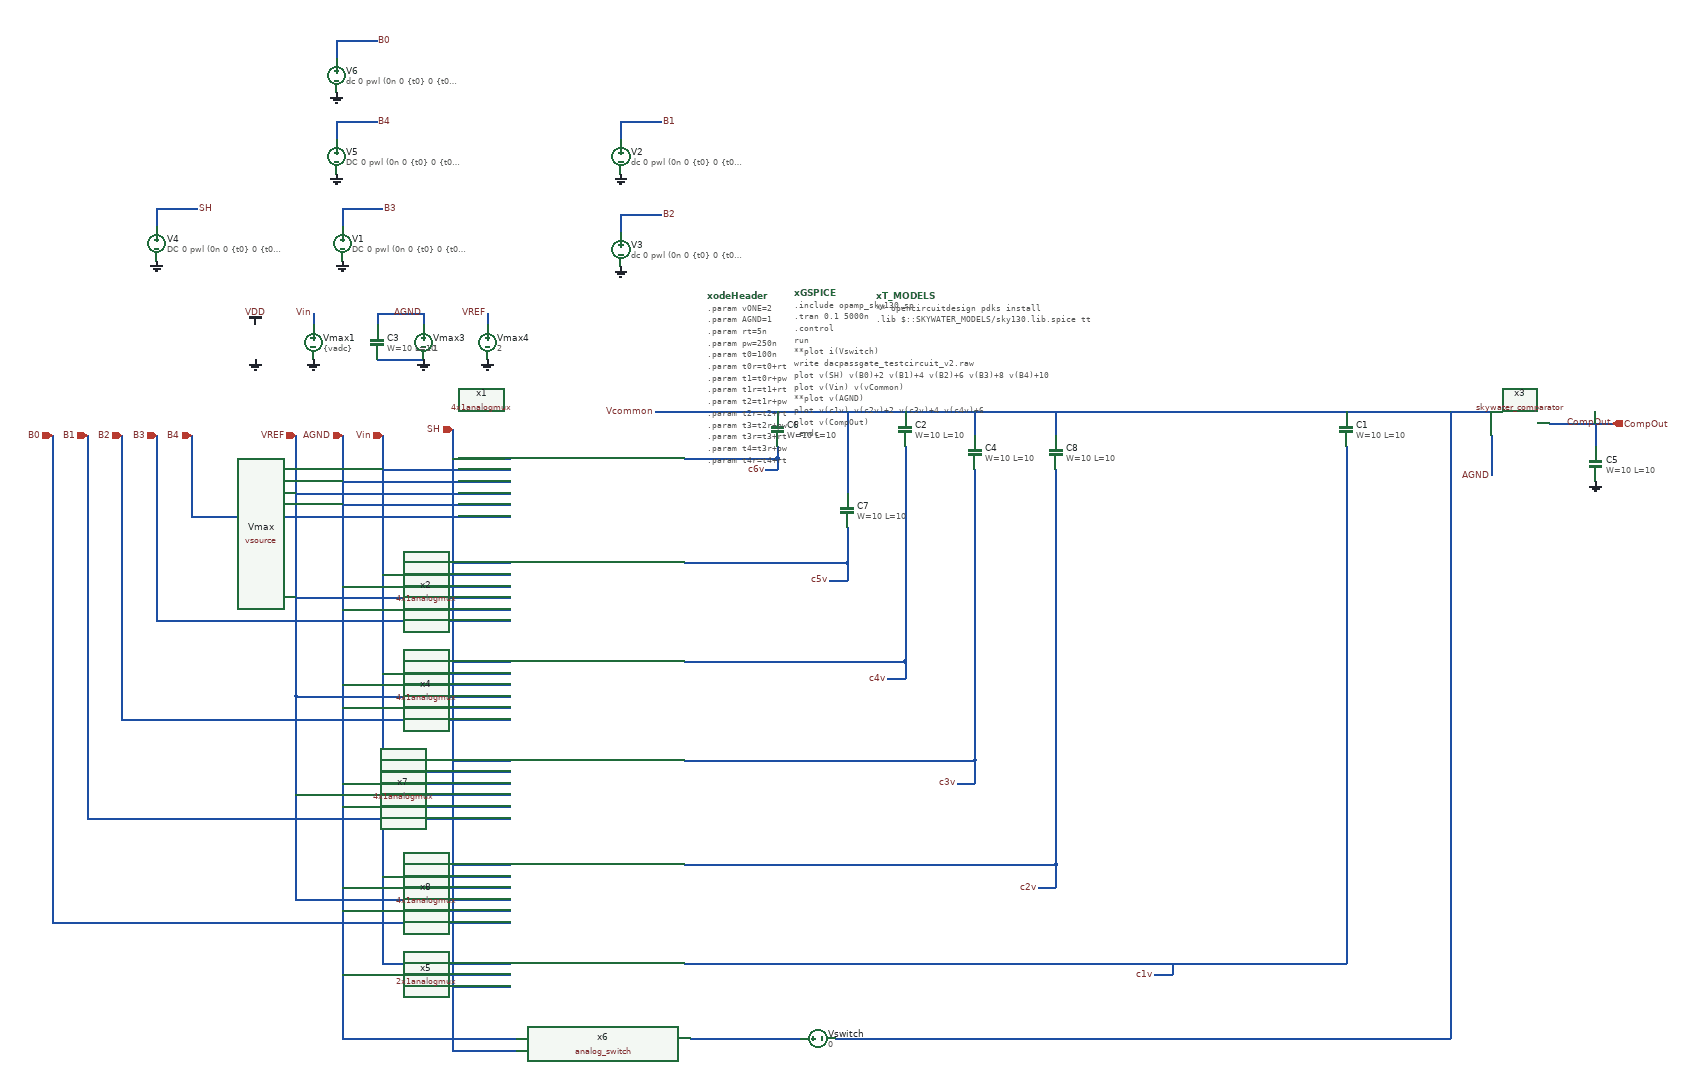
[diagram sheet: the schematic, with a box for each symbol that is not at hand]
v {xschem version=3.0.0 file_version=1.2 

* Copyright 2021 Stefan Frederik Schippers
* 
* Licensed under the Apache License, Version 2.0 (the "License");
* you may not use this file except in compliance with the License.
* You may obtain a copy of the License at
*
*     https://www.apache.org/licenses/LICENSE-2.0
*
* Unless required by applicable law or agreed to in writing, software
* distributed under the License is distributed on an "AS IS" BASIS,
* WITHOUT WARRANTIES OR CONDITIONS OF ANY KIND, either express or implied.
* See the License for the specific language governing permissions and
* limitations under the License.

}
G {}
K {}
V {}
S {}
E {}
N -10 -190 520 -190 { lab=Vcommon}
N 1150 -190 1260 -190 { lab=Vcommon}
N 1260 -150 1260 -80 { lab=AGND}
N 1360 -170 1430 -170 { lab=CompOut}
N -770 -360 -770 -340 { lab=Vin}
N -580 -360 -580 -340 { lab=AGND}
N -1040 -540 -1040 -510 { lab=SH}
N -1040 -540 -970 -540 { lab=SH}
N 1430 -170 1470 -170 { lab=CompOut}
N 1440 -170 1440 -130 { lab=CompOut}
N -470 -360 -470 -340 { lab=VREF}
N -50 -190 -10 -190 { lab=Vcommon}
N 680 780 710 780 { lab=c1v}
N 710 760 710 780 { lab=c1v}
N 250 -130 250 240 { lab=c4v}
N -50 240 250 240 { lab=c4v}
N -720 -540 -720 -510 { lab=B3}
N -720 -540 -650 -540 { lab=B3}
N 250 240 250 270 { lab=c4v}
N 220 270 250 270 { lab=c4v}
N -240 -530 -240 -500 { lab=B2}
N -240 -530 -170 -530 { lab=B2}
N 120 100 140 100 { lab=c5v}
N -50 -110 30 -110 { lab=c6v}
N 30 -130 30 -110 { lab=c6v}
N -730 -690 -730 -660 { lab=B4}
N -730 -690 -660 -690 { lab=B4}
N 30 -110 30 -90 { lab=c6v}
N 10 -90 30 -90 { lab=c6v}
N 150 10 150 70 { lab=c5v}
N 150 -190 150 -50 { lab=Vcommon}
N -180 -190 -50 -190 { lab=Vcommon}
N -650 -150 -650 720 { lab=Vin}
N -720 -150 -720 720 { lab=AGND}
N -530 -160 -530 730 { lab=SH}
N -1040 -150 -1040 160 { lab=B3}
N -1100 -150 -1100 340 { lab=B2}
N -530 -110 -440 -110 { lab=SH}
N -530 70 -430 70 { lab=SH}
N -530 240 -430 240 { lab=SH}
N -980 -10 -440 -10 { lab=B4}
N -1040 170 -430 170 { lab=B3}
N -1100 340 -430 340 { lab=B2}
N -1040 160 -1040 170 { lab=B3}
N -650 -90 -440 -90 { lab=Vin}
N -650 90 -430 90 { lab=Vin}
N -650 260 -430 260 { lab=Vin}
N -130 240 -50 240 { lab=c4v}
N -720 -70 -450 -70 { lab=AGND}
N -450 -70 -440 -70 { lab=AGND}
N -720 110 -430 110 { lab=AGND}
N -720 280 -430 280 { lab=AGND}
N -720 -30 -440 -30 { lab=AGND}
N -800 -50 -440 -50 { lab=VREF}
N -720 150 -430 150 { lab=AGND}
N -800 130 -430 130 { lab=VREF}
N -800 300 -430 300 { lab=VREF}
N -720 320 -430 320 { lab=AGND}
N -800 -150 -800 300 { lab=VREF}
N -120 890 -50 890 { lab=#net1}
N -980 -150 -980 -10 { lab=B4}
N 150 70 150 100 { lab=c5v}
N 140 100 150 100 { lab=c5v}
N -40 70 150 70 { lab=c5v}
N -50 890 70 890 { lab=#net1}
N -660 -360 -580 -360 { lab=AGND}
N -660 -360 -660 -340 { lab=AGND}
N -660 -280 -580 -280 { lab=GND}
N -130 760 380 760 {
lab=c1v}
N 130 890 580 890 {
lab=Vcommon}
N -720 780 -430 780 {
lab=AGND}
N -720 890 -420 890 {
lab=AGND}
N -720 720 -720 890 {
lab=AGND}
N -650 760 -430 760 {
lab=Vin}
N -650 720 -650 760 {
lab=Vin}
N -530 800 -430 800 {
lab=SH}
N -530 910 -420 910 {
lab=SH}
N -530 730 -530 910 {
lab=SH}
N -530 410 -430 410 {
lab=SH}
N -530 590 -430 590 {
lab=SH}
N -650 610 -430 610 {
lab=Vin}
N -130 410 370 410 {
lab=c3v}
N 370 -90 370 410 {
lab=c3v}
N 370 -190 370 -150 {
lab=Vcommon}
N 520 -190 1150 -190 {
lab=Vcommon}
N -130 590 510 590 {
lab=c2v}
N 510 -90 510 590 {
lab=c2v}
N 510 -190 510 -150 {
lab=Vcommon}
N -650 430 -430 430 {
lab=Vin}
N -720 450 -430 450 {
lab=AGND}
N -720 630 -430 630 {
lab=AGND}
N -720 490 -430 490 {
lab=AGND}
N -720 670 -430 670 {
lab=AGND}
N -800 650 -430 650 {
lab=VREF}
N -800 300 -800 650 {
lab=VREF}
N -800 470 -430 470 {
lab=VREF}
N -1160 510 -430 510 {
lab=B1}
N -1160 -150 -1160 510 {
lab=B1}
N -1220 690 -430 690 {
lab=B0}
N -1220 -150 -1220 690 {
lab=B0}
N 580 890 1190 890 {
lab=Vcommon}
N 1190 -190 1190 890 {
lab=Vcommon}
N 510 590 510 610 { lab=c2v}
N 480 630 510 630 { lab=c2v}
N 510 610 510 630 { lab=c2v}
N 370 410 370 430 { lab=c3v}
N 340 450 370 450 { lab=c3v}
N 370 430 370 450 { lab=c3v}
N 380 760 1010 760 {
lab=c1v}
N 1010 -130 1010 760 {
lab=c1v}
N -240 -690 -240 -660 { lab=B1}
N -240 -690 -170 -690 { lab=B1}
N -730 -830 -730 -800 { lab=B0}
N -730 -830 -660 -830 { lab=B0}
N -440 -110 -430 -110 {
lab=SH}
N -440 -90 -430 -90 {
lab=Vin}
N -440 -70 -430 -70 {
lab=AGND}
N -440 -50 -430 -50 {
lab=VREF}
N -440 -30 -430 -30 {
lab=AGND}
N -440 -10 -430 -10 {
lab=B4}
N -130 -110 -50 -110 {
lab=c6v}
N -130 70 -40 70 {
lab=c5v}
C {symbols/code.sym} 60 -395 0 0 {name=xGSPICE
only_toplevel=true
value="
.include "opamp_sky130.sp"

.tran 0.1 5000n
.control
run
**plot i(Vswitch)
write dacpassgate_testcircuit_v2.raw
plot v(SH) v(B0)+2 v(B1)+4 v(B2)+6 v(B3)+8 v(B4)+10
plot v(Vin)  v(vCommon) 
**plot v(AGND)
plot v(c1v) v(c2v)+2 v(c3v)+4 v(c4v)+6
plot v(CompOut)
.endc
" }
C {symbols/code.sym} 200 -390 0 0 {name=xT_MODELS
only_toplevel=true
format="tcleval( @value )"
value="
** opencircuitdesign pdks install
.lib $::SKYWATER_MODELS/sky130.lib.spice tt

"
spice_ignore=false}
C {symbols/vsource.sym} -870 -310 0 0 {name=Vmax value=2}
C {symbols/gnd.sym} -870 -280 0 0 {name=l3 lab=GND}
C {symbols/vdd.sym} -870 -340 0 0 {name=l4 lab=VDD}
C {symbols/cap_mim_m3_1.sym} 1010 -160 0 0 {name=C1 model=cap_mim_m3_1 W=10 L=10 MF=1 spiceprefix=X}
C {symbols/lab_wire.sym} 1260 -80 0 0 {name=l6 sig_type=std_logic lab=AGND}
C {symbols/vsource.sym} -770 -310 0 0 {name=Vmax1 value=\{vadc\}}
C {symbols/gnd.sym} -770 -280 0 0 {name=l14 lab=GND}
C {symbols/vsource.sym} -580 -310 0 0 {name=Vmax3 value=1}
C {symbols/gnd.sym} -580 -280 0 0 {name=l18 lab=GND}
C {symbols/lab_wire.sym} -770 -360 0 0 {name=l17 sig_type=std_logic lab=Vin}
C {symbols/lab_wire.sym} -580 -360 0 0 {name=l20 sig_type=std_logic lab=AGND}
C {symbols/vsource.sym} -1040 -480 0 0 {name=V4 value="DC 0 pwl (0n 0 \{t0\} 0 \{t0r\} 2 \{t1\} 2 \{t1r\} 0)"}
C {symbols/gnd.sym} -1040 -450 0 0 {name=l21 lab=GND}
C {symbols/lab_pin.sym} -970 -540 0 1 {name=x22 sig_type=std_logic lab=SH}
C {symbols/cap_mim_m3_1.sym} 1440 -100 0 0 {name=C5 model=cap_mim_m3_1 W=10 L=10 MF=1 spiceprefix=X}
C {symbols/gnd.sym} 1440 -70 0 0 {name=l29 lab=GND}
C {symbols/lab_wire.sym} 1470 -170 0 0 {name=l30 sig_type=std_logic lab=CompOut}
C {symbols/vsource.sym} -470 -310 0 0 {name=Vmax4 value=2}
C {symbols/gnd.sym} -470 -280 0 0 {name=l31 lab=GND}
C {symbols/lab_wire.sym} -470 -360 0 0 {name=l32 sig_type=std_logic lab=VREF}
C {symbols/lab_wire.sym} -180 -190 0 0 {name=l33 sig_type=std_logic lab=Vcommon}
C {symbols/lab_wire.sym} 680 780 0 0 {name=l37 sig_type=std_logic lab=c1v}
C {symbols/cap_mim_m3_1.sym} 250 -160 0 0 {name=C2 model=cap_mim_m3_1 W=10 L=10 MF=4 spiceprefix=X}
C {symbols/vsource.sym} -720 -480 0 0 {name=V1 value="DC 0 pwl (0n 0 \{t0\} 0 \{t0r\} 2 \{t1\} 2 \{t1r\} 0 \{t4\} 0 \{t4r\} 2 \{t5\} 2 \{t5r\} \{b1d\})"}
C {symbols/gnd.sym} -720 -450 0 0 {name=l8 lab=GND}
C {symbols/lab_pin.sym} -650 -540 0 1 {name=x11 sig_type=std_logic lab=B3}
C {symbols/lab_wire.sym} 220 270 0 0 {name=l23 sig_type=std_logic lab=c4v}
C {skywater_comparator.sym} 1240 -220 2 1 {name=x3}
C {symbols/vsource.sym} -240 -470 0 0 {name=V3 value="dc 0 pwl (0n 0 \{t0\} 0 \{t0r\} 2 \{t1\} 2 \{t1r\} 0 \{t6\} 0 \{t6r\} 2 \{t7\} 2 \{t7r\} \{b0d\})"}
C {symbols/gnd.sym} -240 -440 0 0 {name=l25 lab=GND}
C {symbols/lab_pin.sym} -170 -530 0 1 {name=x26 sig_type=std_logic lab=B2}
C {symbols/lab_wire.sym} 120 100 0 0 {name=l27 sig_type=std_logic lab=c5v}
C {symbols/vsource.sym} -730 -630 0 0 {name=V5 value="DC 0 pwl (0n 0 \{t0\} 0 \{t0r\} 2 \{t1\} 2 \{t1r\} 0 \{t2\} 0 \{t2r\} 2 \{t3\} 2 \{t3r\} \{b2d\})"}
C {symbols/gnd.sym} -730 -600 0 0 {name=l34 lab=GND}
C {symbols/lab_pin.sym} -660 -690 0 1 {name=x35 sig_type=std_logic lab=B4}
C {symbols/lab_wire.sym} 10 -90 0 0 {name=l36 sig_type=std_logic lab=c6v}
C {symbols/cap_mim_m3_1.sym} 30 -160 0 0 {name=C6 model=cap_mim_m3_1 W=10 L=10 MF=16 spiceprefix=X}
C {symbols/cap_mim_m3_1.sym} 150 -20 0 0 {name=C7 model=cap_mim_m3_1 W=10 L=10 MF=8 spiceprefix=X}
C {symbols/code.sym} -90 -390 0 0 {name=xodeHeader only_toplevel=true place=header
value="
.param vONE=2
.param AGND=1
.param rt=5n
.param pw=250n
.param t0=100n
.param t0r=t0+rt
.param t1=t0r+pw
.param t1r=t1+rt
.param t2=t1r+pw
.param t2r=t2+rt
.param t3=t2r+pw
.param t3r=t3+rt
.param t4=t3r+pw
.param t4r=t4+rt
.param t5=t4r+pw
.param t5r=t5+rt
.param t6=t5r+pw
.param t6r=t6+rt
.param t7=t6r+pw
.param t7r=t7+rt
.param t8=t7r+pw
.param t8r=t8+rt
.param t9=t8r+pw
.param t9r=t9+rt
.param b2d=VONE
.param b1d=0
.param b0d=VONE
.param vadc=(b2d/4)+(b1d/8)+(b0d/16)+AGND

"}
C {4x1analogmux.sym} -280 -60 0 0 {name=x1}
C {4x1analogmux.sym} -280 120 0 0 {name=x2}
C {4x1analogmux.sym} -280 290 0 0 {name=x4}
C {symbols/ipin.sym} -650 -150 1 0 {name=p2 lab=Vin}
C {symbols/ipin.sym} -720 -150 1 0 {name=p3 lab=AGND}
C {symbols/ipin.sym} -800 -150 1 0 {name=p4 lab=VREF}
C {symbols/ipin.sym} -530 -160 1 0 {name=p6 lab=SH}
C {symbols/ipin.sym} -1100 -150 1 0 {name=p8 lab=B2}
C {symbols/ipin.sym} -1040 -150 1 0 {name=p9 lab=B3}
C {symbols/ipin.sym} -980 -150 1 0 {name=p10 lab=B4}
C {2x1analogmux.sym} -280 780 0 0 {name=x5}
C {analog_switch.sym} -270 900 0 0 {name=x6}
C {symbols/vsource.sym} 100 890 3 0 {name=Vswitch value=0}
C {symbols/cap_mim_m3_1.sym} -660 -310 0 0 {name=C3 model=cap_mim_m3_1 W=10 L=10 MF=1 spiceprefix=X}
C {symbols/opin.sym} 1470 -170 0 0 {name=p1 lab=CompOut}
C {4x1analogmux.sym} -280 460 0 0 {name=x7}
C {4x1analogmux.sym} -280 640 0 0 {name=x8}
C {symbols/cap_mim_m3_1.sym} 370 -120 0 0 {name=C4 model=cap_mim_m3_1 W=10 L=10 MF=2 spiceprefix=X}
C {symbols/cap_mim_m3_1.sym} 510 -120 0 0 {name=C8 model=cap_mim_m3_1 W=10 L=10 MF=1 spiceprefix=X}
C {symbols/ipin.sym} -1160 -150 1 0 {name=p5 lab=B1}
C {symbols/ipin.sym} -1220 -150 1 0 {name=p7 lab=B0}
C {symbols/lab_wire.sym} 480 630 0 0 {name=l1 sig_type=std_logic lab=c2v}
C {symbols/lab_wire.sym} 340 450 0 0 {name=l2 sig_type=std_logic lab=c3v}
C {symbols/vsource.sym} -240 -630 0 0 {name=V2 value="dc 0 pwl (0n 0 \{t0\} 0 \{t0r\} 2 \{t1\} 2 \{t1r\} 0 \{t7\} 0 \{t7r\} 2 \{t8\} 2 \{t8r\} \{b0d\})"}
C {symbols/gnd.sym} -240 -600 0 0 {name=l5 lab=GND}
C {symbols/lab_pin.sym} -170 -690 0 1 {name=x9 sig_type=std_logic lab=B1}
C {symbols/vsource.sym} -730 -770 0 0 {name=V6 value="dc 0 pwl (0n 0 \{t0\} 0 \{t0r\} 2 \{t1\} 2 \{t1r\} 0 \{t8\} 0 \{t8r\} 2 \{t9\} 2 \{t9r\} \{b0d\})"}
C {symbols/gnd.sym} -730 -740 0 0 {name=l7 lab=GND}
C {symbols/lab_pin.sym} -660 -830 0 1 {name=x10 sig_type=std_logic lab=B0}
